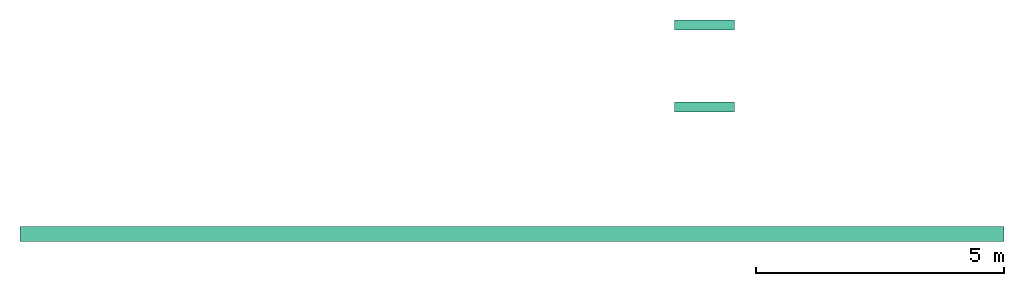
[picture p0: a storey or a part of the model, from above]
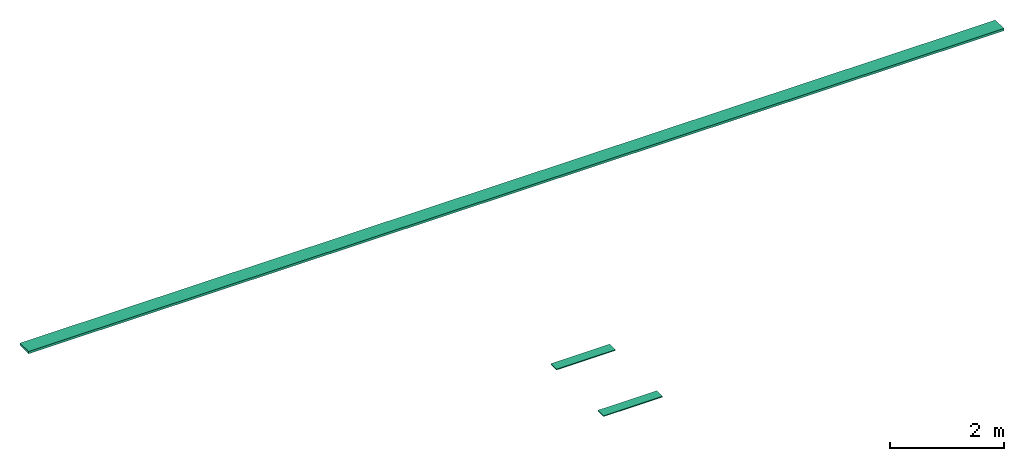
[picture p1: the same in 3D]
Properties of the parts of a building model (IFC2X3)

# File
Description: ViewDefinition [CoordinationView_V2.0]
File name: 20-10
Time: 2021-08-31T15:09:17
Written by: The EXPRESS Data Manager Version 5.02.0100.07 : 28 Aug 2013
Made in: 20200210_1400(x64) - Exporter 20.2.12.1 - Alternate UI 20.2.12.1
Comment: STEP Physical File produced by: The EXPRESS Data Manager Version 5.02.0100.07 : 28 Aug 2013 * Module: EDMstepFileFactory/EDMstandAlone * Creation date: Tue Aug 31 15:09:17 2021 * Host: KAWESQAR * Database: C:\Users\MANONB~1\AppData\Local\Temp\185624fe-82f3-48ab-880a-5ea0e2c92366\1c60d298-b767-46ab-aa57-350fe60cc4c5\ifc * Database version: 5507 * Database creation date: Tue Aug 31 15:09:05 2021 * Schema: IFC2X3 * Model: DataRepository.ifc * Model creation date: Tue Aug 31 15:09:05 2021 * Header model: DataRepository.ifc_HeaderModel * Header model creation date: Tue Aug 31 15:09:05 2021 * EDMuser: sdai-user * EDMgroup: sdai-group * License ID and type: 5605 : Permanent license. Expiry date: * EDMstepFileFactory options: 020000

# IfcProject, 20-10
LongName: OPERATION

# IfcSite, Default
RefLatitude: 48, 51, 57, 604064; RefLongitude: 2, 19, 58, 799800; RefElevation: 0 m

# IfcBuilding
Pset_BuildingCommon - NumberOfStoreys: 10
Pset_ProductRequirements - Category: Project Information

# IfcBuildingStorey: Level:Pointe 8 mm, 03_R+2_EL
LongName: 03_R+2_EL; Elevation: 7.83 m
Pset_ProductRequirements - Name: 03_R+2_EL; Category: Levels
Pset_AirSideSystemInformation - Name: 03_R+2_EL

# IfcBuildingStorey: Niveau:911002-NIV_nom.topo (6)
Pset_ProductRequirements - Category: Levels
Name | LongName | Elevation (m) | Pset_AirSideSystemInformation, Name = Pset_ProductRequirements, Name
S02 | S02 | -4.62 | STR-SS01 Fini
S01 | S01 | -0.4 | STR-FOND RDC
S01 | S01 | -0.06 | STR-RDC Brut
S01 | S01 | 0 | STR-RDC Fini
01 | 01 | 4.27 | STR-R+1
01 | 01 | 7.55 | STR-R+2

# IfcBuildingElementProxy: TD (5)
Type - Pset_BuildingElementProxyCommon - Reference: TD
Type - Pset_ProductRequirements - Category: EL_FR_PANEL_RECTANGLE
Type - Pset_QuantityTakeOff - Reference: TD
Pset_BuildingElementProxyCommon - sets with these values: 2
Pset_ProductRequirements - Category: Electrical Equipment
Name (Tableau divisionaire:...) | In
TD 0.1:7791674 | S02
TD 0.2:8645110 | S02
TD 1.2:8681680 | 01
TD 1.1:8715392 | 01
TD 2.1:8715395 | 03_R+2_EL

# IfcBuildingElementProxy: TGBT, TGBT:TGBT, 230 V/400 V, Three Phase, 4 Wires, Star:7914592
In: S02
Type - Pset_BuildingElementProxyCommon - Reference: TGBT
Type - Pset_ProductRequirements - Category: EL_FR_PANEL_RECTANGLE
Type - Pset_QuantityTakeOff - Reference: TGBT
Pset_BuildingElementProxyCommon - sets with these values: 2
Pset_ProductRequirements - Category: Electrical Equipment

# IfcBuildingElementProxy: VDA - Designed for circulation applications with switches and routers - 42U - 2000x600x1000, IT-racks_Schneider-Electric_Actassi_VDA -Functional-and-adapted-for-evolution:VDA - Designed for circulation applications with switches and routers - 42U - 2000x600x1000:8654036
In: S02
Type - Material: UHMW, Black, Glass, RAL 7035, Schneider Clearance Material
Type - Pset_BuildingElementProxyCommon - Reference: VDA - Designed for circulation applications with switches and routers - 42U - 2000x600x1000
Type - Pset_ManufacturerTypeInformation - Manufacturer: © Schneider Electric
Type - Pset_ProductRequirements - Category: Electrical Equipment
Type - Pset_QuantityTakeOff - Reference: VDA - Designed for circulation applications with switches and routers - 42U - 2000x600x1000
Pset_BuildingElementProxyCommon - sets with these values: 2

# IfcDistributionControlElement: Incendie_Bapi, INT_BAPI:Incendie_Bapi:7913407
In: S02
Type - Material: Color RGB 060-060-060, Color RGB 192-192-192, Color RGB 165-165-165
Pset_ProductRequirements - Category: Fire Alarm Devices
Pset_QuantityTakeOff - Reference: Incendie_Bapi

# IfcDistributionControlElement: Incendie_Centrale Incendie, INT_Centrale Incendie:Incendie_Centrale Incendie:8747964
In: S01
Pset_ProductRequirements - Category: Fire Alarm Devices
Pset_QuantityTakeOff - Reference: Incendie_Centrale Incendie

# IfcDistributionControlElement: Incendie_Diffuseur sonore (7)
Type - Material: Default grid, White Plastic
Pset_ProductRequirements - Category: Fire Alarm Devices
Pset_QuantityTakeOff - Reference: Incendie_Diffuseur sonore
Name (INT_DIffuseur sonore:Incendie_Diffuseur sonore:...) | In
8742318 | S01
8742320 | S01
8742322 | 01
8742324 | 01
8742326 | S02
8742328 | S02
8742329 | 03_R+2_EL

# IfcDistributionControlElement: Incendie_Déclenheur manuel (10)
Pset_ProductRequirements - Category: Fire Alarm Devices
Pset_QuantityTakeOff - Reference: Incendie_Déclenheur manuel
Name (INT_Déclenheur manuel:Incendie_Déclenheur manuel:...) | In
8719832 | S01
8719834 | S01
8719836 | S01
8719840 | 01
8719841 | 01
8719847 | 03_R+2_EL
8719848 | 03_R+2_EL
8756174 | S02
8756181 | S02
8756355 | S02

# IfcDistributionControlElement: Incendie_Flash (9)
Type - Material: Red plastic
Pset_ProductRequirements - Category: Fire Alarm Devices
Pset_QuantityTakeOff - Reference: Incendie_Flash
Name (INT_Flash:Incendie_Flash:...) | In
7744268 | 01
7744298 | 01
7789376 | S01
7789378 | S01
7790916 | S01
7796727 | S02
7796759 | S02
8666191 | 01
8666193 | 01

# IfcDistributionPort (1167)
Description: Flow; FlowDirection: SOURCEANDSINK
Name
InPort_7741705
OutPort_7742182
InPort_7742182
OutPort_7742196
Port_8683754
Port_8741130
Port_7744198
Port_8741123
Port_8741122
Port_7744183
Port_8741120
Port_7744125
Port_8741121
Port_7744142
Port_8741125
Port_7744254
Port_8741124
Port_7744211
Port_7744268
Port_7744298
Port_7744357
2 x Port_7744402
Port_7744631
Port_7744660
Port_7744688
Port_7744747
Port_7744756
Port_7744834
Port_7744846
2 x Port_7769064
Port_7769260
InPort_7769260
2 x OutPort_7778175
2 x Port_7769269
Port_7777599
Port_7777611
Port_7777712
Port_7777721
Port_7777762
Port_7777803
Port_7777885
2 x Port_7777949
Port_7777958
Port_7777965
Port_7777990
Port_7778025
Port_7778034
Port_7778035
Port_7778163
3 x InPort_7778163
OutPort_7876509
OutPort_8675102
Port_7778212
InPort_7778212
2 x OutPort_7778231
3 x InPort_7778221
OutPort_8675103
Port_7778221
2 x OutPort_7913418
Port_7785804
Port_7785842
Port_7785863
Port_7785870
Port_7785947
Port_7785954
Port_7789052
Port_7789136
Port_7789358
InPort_7789362
OutPort_7791303
Port_8740919
Port_7791514
Port_8740922
Port_7791554
Port_8740915
Port_7791263
Port_7789376
Port_7789378
Port_7789380
Port_7789384
Port_7789387
Port_7790916
Port_7791248
Port_8740914
InPort_7791303
OutPort_7791401
Port_7791540
Port_8740921
InPort_7791401
2 x OutPort_7791412
InPort_7791411
Port_7791674
2 x Port_7792699
2 x Port_7792700
Port_7792762
Port_7792832
Port_7792934
Port_7793028
Port_7793156
Port_8740822
Port_7795050
2 x InPort_7793805
OutPort_7793830
OutPort_7793816
Port_7795005
Port_8740819
InPort_7793865
OutPort_7793880
Port_8740825
Port_7795091
InPort_7793897
OutPort_7793899
Port_8740828
Port_7795136
Port_7795076
Port_8740824
Port_7795063
Port_8740823
Port_7795254
Port_7795328
Port_7795365
Port_7795432
Port_7795881
Port_7795892
Port_7795962
Port_8740829
Port_7796375
Port_7796386
Port_8740830
Port_8740831
Port_7796458
Port_8740832
Port_7796549
Port_7796560
Port_8740833
Port_7796626
Port_7796727
Port_7796759
Port_7796838
Port_7796843
Port_7810207
Port_8740835
Port_7810208
Port_8740836
Port_7876471
Port_7876472
Port_7876473
Port_7876475
Port_7876484
InPort_7876486
OutPort_7876488
Port_8740861
Port_7876490
InPort_7876492
OutPort_7876494
Port_8740867
Port_7876508
Port_7876507
Port_8740866
InPort_7876497
OutPort_7876499
Port_8740865
Port_7876506
Port_7876509
InPort_7876509
OutPort_7913447
InPort_7876520
2 x OutPort_7913417
Port_7876520
Port_7877531
InPort_7901673
OutPort_7901679
Port_7901717
Port_8740871
Port_7901730
Port_8740876
2 x Port_7901684
Port_7901685
Port_7901687
Port_7901688
Port_7901689
Port_7901690
Port_7901691
Port_7901692
Port_7901728
InPort_7901718
OutPort_7901719
Port_8740874
Port_8740875
Port_7901729
Port_7901731
InPort_7901723
OutPort_7901724
Port_8740877
Port_8740878
Port_7901732
2 x Port_7901733
Port_7901734
Port_7901736
Port_7901737
Port_7901738
Port_7901739
Port_7901740
Port_7901741
2 x Port_7901742
Port_7901743
Port_7901745
Port_7901746
Port_7901747
Port_7901748
Port_7901749
Port_7901750
2 x Port_7901751
Port_7901752
Port_7901754
Port_7901755
Port_7901756
Port_7901757
Port_7901758
Port_7901759
2 x Port_7901801
Port_7901802
Port_7901804
Port_7901805
Port_7901806
Port_7901807
Port_7901808
Port_7901809
Port_8740880
Port_7902684
Port_7902669
Port_8740879
Port_7902081
Port_7902106
Port_7902208
Port_7902437
Port_7913393
Port_7913400
Port_7913403
Port_7913406
Port_7913407
2 x InPort_7913409
2 x OutPort_7913464
OutPort_7913458
2 x InPort_7913410
OutPort_7913459
2 x OutPort_7913463
2 x InPort_7913411
2 x OutPort_7913415
2 x InPort_7913414
2 x OutPort_7913420
2 x InPort_7913416
InPort_7913417
2 x InPort_7913423
OutPort_7913431
InPort_7913431
OutPort_7913433
InPort_7913433
2 x OutPort_7913435
2 x InPort_7913434
2 x OutPort_7913437
2 x InPort_7913436
2 x OutPort_7913440
2 x InPort_7913439
2 x OutPort_7913446
2 x InPort_7913445
2 x OutPort_7913448
InPort_7913447
2 x Port_7913458
InPort_7913458
OutPort_8645113
InPort_7913459
OutPort_8645114
2 x Port_7913459
Port_7914592
Port_8750771
2 x InPort_7914593
OutPort_7914599
2 x OutPort_8734681
Port_8270898
Port_8270900
Port_8277180
Port_8277182
Port_8277183
InPort_8277184
2 x OutPort_8277198
Port_8277184
2 x InPort_8277187
2 x OutPort_8277191
Port_8277190
InPort_8277190
Port_8277192
Port_8277193
Port_8277194
Port_8277195
Port_8277199
Port_8277200
Port_8277201
Port_8277202
Port_8277203
Port_8277204
Port_8277205
Port_8277206
Port_8277207
Port_8277208
Port_8277209
Port_8277210
Port_8277211
Port_8277212
Port_8277213
Port_8277214
Port_8277215
Port_8277216
Port_8277217
Port_8277218
Port_8277219
Port_8277358
Port_8277359
Port_8277360
Port_8277361
Port_8277362
Port_8277363
Port_8277364
Port_8277487
Port_8277488
Port_8277489
Port_8277490
Port_8277491
Port_8277492
Port_8277493
Port_8277500
Port_8277501
Port_8277502
Port_8277503
Port_8277504
Port_8277505
Port_8277506
Port_8277512
Port_8277513
Port_8277514
Port_8277515
Port_8277516
Port_8277517
Port_8277518
Port_8277529
Port_8277530
Port_8277531
Port_8277532
Port_8277533
Port_8277534
Port_8277535
Port_8277570
Port_8277633
Port_8281313
Port_8281360
Port_8281379
Port_8281695
Port_8281696
Port_8281786
Port_8289758
Port_8297719
Port_8297810
Port_8297825
Port_8297848
Port_8317719
Port_8317720
Port_8317721
Port_8318129
Port_8318138
Port_8318201
Port_8318212
Port_8318221
Port_8318230
Port_8318244
Port_8318246
Port_8318248
Port_8318250
Port_8318252
Port_8318254
Port_8318371
Port_8318383
InPort_8318572
OutPort_8318608
InPort_8318608
OutPort_8318626
Port_8318745
Port_8740956
Port_8319005
Port_8319007
Port_8319008
Port_8319009
Port_8319034
InPort_8319157
OutPort_8319195
InPort_8319195
OutPort_8320982
Port_8321050
Port_8321082
Port_8321099
Port_8321119
Port_8321156
Port_8632143
Port_8632144
Port_8632147
Port_8632148
Port_8632155
Port_8632162
Port_8632166
Port_8632167
Port_8632168
Port_8632169
Port_8632171
Port_8632175
Port_8632177
Port_8632179
Port_8632181
Port_8632204
Port_8632205
Port_8645110
Port_8645113
Port_8645114
2 x Port_8645142
Port_8645143
Port_8645145
Port_8645146
Port_8645147
Port_8645148
Port_8645149
Port_8645334
Port_8645335
Port_8645336
Port_8645579
Port_8645580
Port_8645581
2 x Port_8645821
Port_8645822
Port_8645824
Port_8645825
Port_8645826
Port_8645827
Port_8645828
Port_8645892
Port_8645905
Port_8645922
Port_8645923
Port_8645931
Port_8645972
Port_8645983
Port_8646006
Port_8646044
Port_8646108
Port_8646135
Port_8646147
Port_8646162
Port_8646165
Port_8646168
Port_8646170
Port_8650504
Port_8650516
Port_8650518
Port_8650525
2 x Port_8650588
Port_8650589
Port_8650591
Port_8650592
Port_8650593
Port_8650594
Port_8650595
Port_8650602
Port_8650604
Port_8650605
Port_8650607
Port_8650609
InPort_8650686
OutPort_8650687
InPort_8650687
OutPort_8650688
InPort_8650811
OutPort_8650812
Port_8650871
Port_8650873
Port_8650874
Port_8650875
Port_8650876
Port_8650877
Port_8650883
Port_8650884
Port_8650885
Port_8650886
Port_8650887
Port_8650888
2 x Port_8665642
Port_8665645
Port_8665646
Port_8665647
Port_8665648
Port_8665649
Port_8665650
2 x Port_8665852
Port_8665855
Port_8665856
Port_8665857
Port_8665858
Port_8665859
Port_8665860
2 x Port_8665933
Port_8665937
Port_8665940
Port_8665941
Port_8666030
Port_8741018
Port_8666187
Port_8666186
Port_8741017
Port_8741015
Port_8666182
Port_8741016
Port_8666183
Port_8666190
Port_8741020
Port_8741019
Port_8666188
Port_8666191
Port_8666193
Port_8666195
Port_8666197
2 x Port_8667869
Port_8667871
Port_8667872
Port_8667873
Port_8667874
Port_8667875
Port_8667876
Port_8674193
InPort_8667969
OutPort_8667970
Port_8741045
InPort_8668206
OutPort_8668207
InPort_8668221
OutPort_8668222
InPort_8668234
OutPort_8668235
InPort_8668245
OutPort_8668246
InPort_8668327
OutPort_8668328
InPort_8668354
OutPort_8668355
InPort_8668381
OutPort_8668382
Port_8668447
Port_8668458
Port_8668472
Port_8668496
Port_8741046
Port_8674273
Port_8674291
Port_8674303
Port_8674603
Port_8741048
Port_8674588
Port_8741047
Port_8674676
Port_8674997
Port_8675016
Port_8675026
Port_8675043
Port_8675046
Port_8675049
Port_8675051
Port_8675102
Port_8675103
2 x InPort_8675104
2 x OutPort_8880330
2 x OutPort_8824633
2 x Port_8675105
2 x Port_8681093
Port_8681095
Port_8681096
Port_8681097
Port_8681098
Port_8681099
Port_8681100
2 x Port_8681101
Port_8681103
Port_8681104
Port_8681105
Port_8681106
Port_8681107
Port_8681108
2 x Port_8681109
Port_8681111
Port_8681112
Port_8681113
Port_8681114
Port_8681115
Port_8681116
Port_8681117
Port_8681118
Port_8681119
Port_8681120
Port_8681121
Port_8681122
Port_8681123
Port_8681124
Port_8681125
Port_8681126
Port_8681127
Port_8681128
Port_8681129
Port_8681130
Port_8681131
Port_8681132
Port_8681133
Port_8681134
Port_8681139
Port_8681140
2 x Port_8681143
Port_8681145
Port_8681146
Port_8681147
Port_8681148
2 x Port_8681154
Port_8681156
Port_8681157
Port_8681158
Port_8681159
Port_8681160
Port_8681161
2 x Port_8681162
Port_8681164
Port_8681165
Port_8681166
Port_8681167
Port_8681168
Port_8681169
2 x Port_8681170
Port_8681172
Port_8681173
Port_8681174
Port_8681175
Port_8681176
Port_8681177
2 x Port_8681178
Port_8681180
Port_8681181
Port_8681182
Port_8681183
Port_8681184
Port_8681185
Port_8681186
Port_8681187
Port_8681188
Port_8681189
Port_8681190
Port_8681191
Port_8681192
Port_8681193
Port_8681194
Port_8681195
Port_8681196
Port_8681197
2 x Port_8681198
Port_8681200
Port_8681201
Port_8681202
Port_8681203
Port_8681204
Port_8681205
2 x Port_8681207
Port_8681209
Port_8681210
Port_8681211
Port_8681212
Port_8681213
Port_8681214
2 x Port_8681215
Port_8681217
Port_8681218
Port_8681219
Port_8681220
Port_8681221
Port_8681222
2 x Port_8681223
Port_8681225
Port_8681226
Port_8681227
Port_8681228
2 x Port_8681229
Port_8681231
Port_8681232
Port_8681233
Port_8681234
Port_8681235
Port_8681236
InPort_8681350
OutPort_8681396
InPort_8681354
OutPort_8681355
Port_8681362
Port_8741083
Port_8681465
Port_8741084
Port_8741090
Port_8681495
Port_8681502
InPort_8681538
OutPort_8681539
Port_8741096
InPort_8681547
OutPort_8822909
Port_8681567
Port_8681573
Port_8681579
Port_8681602
Port_8681608
Port_8681614
Port_8681620
Port_8681626
Port_8681680
2 x InPort_8683758
OutPort_8683759
2 x OutPort_8688980
InPort_8683759
OutPort_8683768
InPort_8683763
OutPort_8683764
InPort_8683764
Port_8688659
2 x InPort_8688800
2 x OutPort_8688810
OutPort_8688801
2 x InPort_8688805
OutPort_8688806
2 x InPort_8688830
2 x OutPort_8688840
OutPort_8688831
InPort_8688835
OutPort_8688836
InPort_8688836
InPort_8691844
OutPort_8691845
Port_8691853
Port_8691888
Port_8710521
2 x Port_8710523 | Group: M531 11
Port_8710527
Port_8710529
Port_8710531
Port_8710533
Port_8710535
Port_8710537
Port_8710539
Port_8710541
Port_8710543
Port_8710546
Port_8710551
Port_8710555
Port_8715392
Port_8715395
Port_8715397
Port_8715398
Port_8715399
Port_8715400
Port_8715401
Port_8715402
Port_8715403
Port_8715404
Port_8715405
Port_8715406
Port_8715407
Port_8715408
Port_8715409
Port_8715410
Port_8715411
Port_8715412
Port_8715413
Port_8715414
Port_8715415
Port_8715416
Port_8715417
Port_8715418
Port_8715419
Port_8715420
Port_8715421
Port_8715422
Port_8715423
Port_8715424
Port_8715425
Port_8715426
Port_8715427
Port_8715428
Port_8715429
Port_8715430
Port_8719832
Port_8719834
Port_8719836
Port_8719840
Port_8719841
Port_8719847
Port_8719848
Port_8719849
Port_8719852
Port_8740893
Port_8723903
Port_8723904
Port_8740894
Port_8723905
Port_8740895
Port_8723906
Port_8734037
Port_8734039
Port_8734041
Port_8734043
Port_8734045
Port_8734212
InPort_8734679
Port_8740897
Port_8734692
Port_8750758
Port_8742318
Port_8742320
Port_8742322
Port_8742324
Port_8742326
Port_8742328
Port_8742329
Port_8742353
Port_8747907
Port_8747913
Port_8747919
Port_8747964
Port_8748015
Port_8748039
Port_8750186
Port_8750603
2 x Port_8750664 | Group: M531 12
2 x Port_8750677 | Group: M531 13
Port_8750823
Port_8750847
Port_8750853
Port_8750859
InPort_8751408
2 x OutPort_8751423
Port_8751408
2 x InPort_8751417
2 x OutPort_8751441
2 x InPort_8751427
2 x OutPort_8751470
InPort_8751458
Port_8751458
Port_8753972
Port_8753975
Port_8753982
Port_8753983
Port_8753986
Port_8753987
Port_8753990
Port_8753991
Port_8755647
InPort_8755505
OutPort_8755559
Port_8756728
InPort_8755559
OutPort_8755570
InPort_8755570
OutPort_8755578
2 x Port_8755763
Port_8755764
Port_8755766
Port_8755767
Port_8755768
Port_8755769
Port_8755770
Port_8755771
Port_8755869
Port_8755871
Port_8755873
Port_8755917
Port_8755945
Port_8755970
Port_8756174
Port_8756181
Port_8756355
Port_8767871
Port_8767872
Port_8767957
Port_8768032
Port_8768043
Port_8768068
Port_8768084
Port_8768119
Port_8768458
Port_8768469
Port_8768478
Port_8768487
Port_8768496
Port_8768507
Port_8768518
Port_8768533
Port_8768542
Port_8768551
Port_8768560
Port_8768569
Port_8768580
Port_8768589
Port_8768598
2 x Port_8798240
Port_8798241
Port_8798243
Port_8798244
Port_8798245
Port_8798246
Port_8798247
Port_8798248
Port_8798345
Port_8823341
2 x Port_8798410
Port_8798412
Port_8798413
Port_8798414
Port_8798415
Port_8798416
Port_8798417
Port_8798418
InPort_8798577
OutPort_8798578
Port_8798621
Port_8798687
Port_8798713
Port_8798722
Port_8798731
Port_8798742
Port_8798753
Port_8798764
Port_8798775
Port_8798786
Port_8798795
Port_8798806
Port_8798817
Port_8798826
Port_8798835
Port_8798848
Port_8798857
Port_8798870
Port_8821109
Port_8821135
Port_8821144
Port_8821153
Port_8821162
Port_8821171
Port_8821180
Port_8821304
Port_8821330
Port_8821364
Port_8821366
Port_8821391
Port_8821392
Port_8821400
Port_8821401
Port_8821415
2 x InPort_8821556
2 x OutPort_8821734
2 x OutPort_8821755
2 x InPort_8821626
2 x OutPort_8821657
2 x InPort_8821648
2 x OutPort_8821672
2 x InPort_8821660
2 x OutPort_8821683
Port_8821675
InPort_8821675
InPort_8821744
Port_8821744
Port_8822402
Port_8822403
Port_8822413
Port_8822414
Port_8822533
Port_8822534
Port_8822545
Port_8822546
Port_8822557
Port_8822558
Port_8822569
Port_8822570
2 x InPort_8824520
2 x OutPort_8880285
2 x OutPort_8824594
2 x Port_8824521
2 x InPort_8824582
2 x OutPort_8824607
2 x InPort_8824597
2 x OutPort_8824636
2 x InPort_8824610
Port_8828758
Port_8828759
Port_8828760
Port_8828761
Port_8828762
Port_8828763
Port_8828764
Port_8828765
Port_8828766
Port_8828767
Port_8828768
Port_8828769
Port_8828770
Port_8828771
Port_8828772
Port_8828773
Port_8828774
Port_8828775
Port_8828776
Port_8828777
Port_8828778
Port_8828779
Port_8828780
Port_8828781
Port_8828782
Port_8828783
Port_8828784
Port_8828786
Port_8828787
Port_8865605
Port_8865611
Port_8866616
Port_8866637
Port_8866665
Port_8866804
Port_8866954
Port_8866969
Port_8877106
Port_8877118
Port_8877124
Port_8877139
Port_8877145
Port_8877151
Port_8877314
2 x InPort_8879930
2 x OutPort_8880289
2 x OutPort_8880291
2 x InPort_8879931
2 x OutPort_8880287
2 x InPort_8879933
Port_8880235
InPort_8880235
2 x InPort_8880314
2 x OutPort_8880333
Port_8880315
InPort_8880315

# IfcFlowFitting: E_Bend_Horizontal_CA_Generic_MEPcontent (8)
Pset_DistributionFlowElementCommon - Reference: E_Bend_Horizontal_CA_Generic_MEPcontent; sets with these values: 2
Pset_ProductRequirements - Category: Cable Tray Fittings
Name (E_Bend_Horizontal_CA_Generic_MEPcontent:E_Bend_Horizontal_CA_Generic_MEPcontent:...) | In
7913415 | S02
7913420 | S02
7913431 | S02
7913435 | S02
7913463 | S02
7913464 | S02
8277191 | S01
8277198 | S01

# IfcFlowFitting: E_Bend_Vertical_Inside_CA_Generic_MEPcontent (8)
Pset_DistributionFlowElementCommon - Reference: E_Bend_Vertical_Inside_CA_Generic_MEPcontent; sets with these values: 2
Pset_ProductRequirements - Category: Cable Tray Fittings
Name (E_Bend_Vertical_Inside_CA_Generic_MEPcontent:E_Bend_Vertical_Inside_CA_Generic_MEPcontent:...) | In
7913437 | S02
7913448 | S02
8751441 | S02
8824607 | 01
8824636 | 01
8880287 | 01
8880291 | 01
8880333 | 01

# IfcFlowFitting: E_Bend_Vertical_Outside_CA_Generic_MEPcontent (11)
Pset_DistributionFlowElementCommon - Reference: E_Bend_Vertical_Outside_CA_Generic_MEPcontent; sets with these values: 2
Pset_ProductRequirements - Category: Cable Tray Fittings
Name (E_Bend_Vertical_Outside_CA_Generic_MEPcontent:E_Bend_Vertical_Outside_CA_Generic_MEPcontent:...) | In
7778175 | 03_R+2_EL
7778231 | 03_R+2_EL
7913440 | S02
7913446 | S02
8751423 | S02
8751470 | S02
8824594 | 01
8824633 | 01
8880285 | 01
8880289 | 01
8880330 | 01

# IfcFlowFitting: E_Connection_CA_Generic_MEPcontent, E_Connection_CA_Generic_MEPcontent:E_Connection_CA_Generic_MEPcontent:8824521
In: 01
Pset_DistributionFlowElementCommon - Reference: E_Connection_CA_Generic_MEPcontent; sets with these values: 2
Pset_ProductRequirements - Category: Cable Tray Fittings

# IfcFlowFitting: E_E6120_Lightning Conductor_Bend_MEPcontent (5)
In: S02
Pset_DistributionFlowElementCommon - Reference: E_E6120_Lightning Conductor_Bend_MEPcontent; sets with these values: 2
Pset_ProductRequirements - Category: Conduit Fittings
Name (E_Lightning Conductor_Bend_MEPcontent:E_E6120_Lightning Conductor_Bend_MEPcontent:...)
8821657
8821672
8821683
8821734
8821755

# IfcFlowFitting: E_Tee_Horizontal_CA_Generic_MEPcontent, E_Tee_Horizontal_CA_Generic_MEPcontent:E_Tee_Horizontal_CA_Generic_MEPcontent:7913417
In: S02
Pset_DistributionFlowElementCommon - Reference: E_Tee_Horizontal_CA_Generic_MEPcontent; sets with these values: 2
Pset_ProductRequirements - Category: Cable Tray Fittings

# IfcFlowFitting: M_Bend_Circular_MEPcontent_Cuivre_2M (3)
In: S02
Type - PredefinedType: BEND
Pset_DistributionFlowElementCommon - Reference: M_Bend_Circular_MEPcontent_Cuivre_2M; sets with these values: 2
Pset_ManufacturerTypeInformation - Manufacturer: Unspecified
Pset_ProductRequirements - Category: Pipe Fittings
Name (M_Bend_Circular_MEPcontent_Cuivre_2M:M_Bend_Circular_MEPcontent_Cuivre_2M:...) | Group
8710523 | M531 11
8750664 | M531 12
8750677 | M531 13

# IfcFlowSegment: Cable Tray with Fittings:Chemins de câbles en treillis_Chemins de câbles en treillis (39)
Pset_DistributionFlowElementCommon - Reference: Chemins de câbles en treillis_Chemins de câbles en treillis; sets with these values: 2
Pset_FlowSegmentDuctSegment - sets with these values: 2
Pset_ManufacturerTypeInformation - Manufacturer: Unspecified
Pset_ProductRequirements - Category: Cable Trays
Name (Cable Tray with Fittings:Chemins de câbles en treillis_Chemins de câbles en treillis:...) | In | Length (m)
7769260 | 01 | 12.6219
7778163 | 01 | 14.0779
7778212 | 01 | 12.6219
7778221 | 01 | 14.5509
7792699 | S01 | 19.8335
7792700 | S02 | 19.9384
7876509 | S02 | 12.653
7876520 | S02 | 8.0316
7913409 | S02 | 5.12579
7913410 | S02 | 4.26001
7913411 | S02 | 3.97459
7913414 | S02 | 16.6468
7913416 | S02 | 3.37523
7913418 | S02 | 4.02137
7913423 | S02 | 5.98814
7913433 | S02 | 20.6547
7913434 | S02 | 3.9629
7913436 | S02 | 0.695139
7913439 | S02 | 0.371697
7913445 | S02 | 0.152074
7913447 | S02 | 0.509213
7913458 | 01 | 11.456
7913459 | 01 | 11.456
8645113 | S01 | 15.3977
8645114 | S01 | 15.3977
8675102 | 01 | 19.8335
8675103 | S01 | 19.8335
8675104 | 01 | 3.01401
8675105 | 01 | 15.3977
8824520 | 01 | 1.66598
8824582 | 01 | 0.205081
8824597 | 01 | 1.23808
8824610 | 01 | 0.205062
8879930 | 01 | 0.205081
8879931 | 01 | 1.23808
8879933 | 01 | 0.205081
8880235 | 01 | 6.09454
8880314 | 01 | 0.205056
8880315 | 01 | 1.23808

# IfcFlowSegment: Cable Tray with Fittings:Goulottes de câbles indéfini_Goulottes de câbles (39)
Pset_DistributionFlowElementCommon - Reference: Goulottes de câbles indéfini_Goulottes de câbles; sets with these values: 2
Pset_FlowSegmentDuctSegment - sets with these values: 2
Pset_ManufacturerTypeInformation - Manufacturer: Unspecified
Pset_ProductRequirements - Category: Cable Trays
Name (Cable Tray with Fittings:Goulottes de câbles indéfini_Goulottes de câbles:...) | In | Length (m)
7744402 | 01 | 1.992
7769064 | 01 | 2.247
7769269 | 01 | 6.768
7777949 | 01 | 6.768
7901684 | S02 | 2.834
7901733 | S02 | 2.66
7901742 | S02 | 2.667
7901751 | S02 | 3.78703
7901801 | S02 | 3.146
8277184 | S01 | 12.9969
8277187 | S01 | 7.90084
8277190 | S01 | 12.9209
8645142 | S01 | 2.041
8645821 | S01 | 6.873
8650588 | 01 | 5.6
8665642 | 01 | 2.749
8665852 | 01 | 3.916
8665933 | 01 | 3.8836
8667869 | 01 | 4.03
8681093 | 01 | 6.736
8681101 | 01 | 3.916
8681109 | 01 | 6.737
8681143 | 01 | 2.739
8681154 | 01 | 3.916
8681162 | 01 | 7.912
8681170 | 01 | 2.419
8681178 | 01 | 2.716
8681198 | 01 | 2.419
8681207 | 01 | 2.749
8681215 | 01 | 7.892
8681223 | 01 | 3.8836
8681229 | 01 | 1.461
8751408 | S02 | 4.69455
8751417 | S02 | 1.0201
8751427 | S02 | 4.3511
8751458 | S02 | 0.289548
8755763 | 01 | 3.61246
8798240 | S01 | 2.859
8798410 | 01 | 1.727

# IfcFlowSegment: Conduit without Fittings:Conduit (6)
In: S02
Pset_DistributionFlowElementCommon - Reference: Conduit; sets with these values: 2
Pset_FlowSegmentDuctSegment - sets with these values: 2
Pset_ProductRequirements - Category: Conduits
Name (Conduit without Fittings:Conduit:...) | Length (m)
8821556 | 3.09092
8821626 | 0.759408
8821648 | 2.24586
8821660 | 3.04233
8821675 | 0.879768
8821744 | 2.32981

# IfcFlowTerminal: Attente (71)
Pset_DistributionFlowElementCommon - Reference: Attente; sets with these values: 2
Pset_ProductRequirements - Category: Electrical Fixtures
Name (INT_Attente électrique:Attente:...) | In
7789052 | 01
7789384 | S01
7796838 | S02
8710521 | S02
8710527 | S02
8710529 | S02
8710531 | S02
8710533 | S02
8710535 | S02
8710537 | S02
8710539 | S02
8710541 | S01
8710543 | S01
8710546 | 01
8710551 | 03_R+2_EL
8710555 | 03_R+2_EL
8719852 | S02
8723906 | S02
8734037 | S01
8734039 | 01
8734041 | 03_R+2_EL
8734043 | 03_R+2_EL
8734045 | 03_R+2_EL
8767871 | 03_R+2_EL
8767872 | 03_R+2_EL
8767957 | S02
8768032 | S02
8768043 | S02
8768068 | S02
8768084 | S02
8768119 | S01
8768458 | S01
8768469 | S01
8768478 | S01
8768487 | S01
8768496 | S01
8768507 | S01
8768518 | S01
8768533 | S01
8768542 | S01
8768551 | S01
8768560 | S01
8768569 | S01
8768580 | S01
8768589 | S01
8768598 | S01
8798687 | 01
8798713 | 01
8798722 | 01
8798731 | 01
8798742 | 01
8798753 | 01
8798764 | 01
8798775 | 01
8798786 | 01
8798795 | 01
8798806 | 01
8798817 | 01
8798826 | 01
8798835 | 01
8798848 | 01
8798857 | 01
8798870 | 01
8821109 | 03_R+2_EL
8821135 | 03_R+2_EL
8821144 | 03_R+2_EL
8821153 | 03_R+2_EL
8821162 | 03_R+2_EL
8821171 | 03_R+2_EL
8821180 | 03_R+2_EL
8821415 | S02

# IfcFlowTerminal: BAEA Type 3 (2)
In: S01
Type - Material: Color RGB 225-225-149, Color RGB 165-165-165
Pset_DistributionFlowElementCommon - Reference: BAEA Type 3; sets with these values: 2
Pset_ProductRequirements - Category: Lighting Fixtures
Name (II_PREF_BAEA:BAEA Type 3:...)
8289758
8297719

# IfcFlowTerminal: BP IP21 (43)
Pset_DistributionFlowElementCommon - Reference: BP IP21; sets with these values: 2
Pset_ProductRequirements - Category: Lighting Devices
Name | In
INT_Inter BP:BP IP21:8723908 | S01
INT_Cmd BA:BP IP21:8733993 | S01
INT_Cmd BA:BP IP21:8733998 | S01
INT_Cmd BA:BP IP21:8733999 | S01
INT_Cmd BA:BP IP21:8734000 | S01
INT_Cmd BA:BP IP21:8734001 | S01
INT_Cmd BA:BP IP21:8734002 | S01
INT_Cmd BA:BP IP21:8734003 | S01
INT_Cmd BA:BP IP21:8734004 | S01
INT_Cmd BA:BP IP21:8734005 | S01
INT_Cmd BA:BP IP21:8734006 | 01
INT_Cmd BA:BP IP21:8734008 | 01
INT_Cmd BA:BP IP21:8734009 | 01
INT_Cmd BA:BP IP21:8734011 | 01
INT_Cmd BA:BP IP21:8734012 | 01
INT_Cmd BA:BP IP21:8734013 | 01
INT_Cmd BA:BP IP21:8734014 | 01
INT_Cmd BA:BP IP21:8734016 | 01
INT_Cmd BA:BP IP21:8734018 | 01
INT_Cmd BA:BP IP21:8734019 | 01
INT_Cmd BA:BP IP21:8734020 | 01
INT_Cmd BA:BP IP21:8734022 | 01
INT_Cmd BA:BP IP21:8734023 | 01
INT_Cmd BA:BP IP21:8734024 | 01
INT_Cmd BA:BP IP21:8734026 | 01
INT_Cmd BA:BP IP21:8734027 | 03_R+2_EL
INT_Cmd BA:BP IP21:8734029 | 03_R+2_EL
INT_Cmd BA:BP IP21:8734030 | 03_R+2_EL
INT_Cmd BA:BP IP21:8734036 | 03_R+2_EL
INT_Cmd BA:BP IP21:8757446 | S02
INT_Cmd BA:BP IP21:8757468 | S02
INT_Cmd BA:BP IP21:8757615 | S02
INT_Cmd BA:BP IP21:8757793 | S02
INT_Cmd BA:BP IP21:8757800 | S02
INT_Cmd BA:BP IP21:8758039 | S02
INT_Cmd BA:BP IP21:8768624 | S01
INT_Cmd BA:BP IP21:8798009 | S01
INT_Cmd BA:BP IP21:8798011 | S01
INT_Cmd BA:BP IP21:8798017 | S01
INT_Cmd BA:BP IP21:8798018 | S01
INT_Cmd BA:BP IP21:8801330 | 03_R+2_EL
INT_Cmd BA:BP IP21:8801430 | 03_R+2_EL
INT_Cmd BA:BP IP21:8811316 | 03_R+2_EL

# IfcFlowTerminal: B_Réglete étanche (25)
Pset_DistributionFlowElementCommon - Reference: B_Réglete étanche; sets with these values: 2
Pset_ProductRequirements - Category: Lighting Fixtures
Name (II_PREF_Type B Réglette étanche:B_Réglete étanche:...) | In
7793730 | S02
7793805 | S02
7793816 | S02
7793830 | S02
7793865 | S02
7793880 | S02
7793897 | S02
7793899 | S02
7793910 | S02
7793925 | S02
7797838 | S02
7797846 | S02
7876486 | S02
7876488 | S02
7876492 | S02
7876494 | S02
7876497 | S02
7876499 | S02
7914593 | S02
7914599 | S02
8723878 | S02
8723880 | S02
8723882 | S02
8734679 | S01
8734681 | S01

# IfcFlowTerminal: Baie de brassage, INT_Baie de Brassage:Baie de brassage:8866969
In: S02
Pset_DistributionFlowElementCommon - Reference: Baie de brassage; sets with these values: 2
Pset_ProductRequirements - Category: Data Devices

# IfcFlowTerminal: CSS-UC-1_Video Package w/Universal Power Pack (2)
In: S02
Type - Classification: F1050900 Other Special Control& Instrumentation (Uniformat); Material: Plastic - Crestron Electronics - B-S - Black Smooth
Pset_DistributionFlowElementCommon - Reference: CSS-UC-1_Video Package w/Universal Power Pack; sets with these values: 2
Pset_ManufacturerTypeInformation - Manufacturer: Crestron Electronics, Inc.
Pset_ProductRequirements - Category: Communication Devices
Name (Digital_Media-Crestron-Mercury-CCS-UC-1:CSS-UC-1_Video Package w/Universal Power Pack:...)
8750186
8750603

# IfcFlowTerminal: Default (37)
Pset_DistributionFlowElementCommon - Reference: Default; sets with these values: 2
Pset_ProductRequirements - Category: Security Devices
Name (E_Reader_Badge 1_F_MEPcontent:Default:...) | In
7785804 | 01
7785842 | 01
7785863 | 01
7785870 | 01
7785947 | 01
7785954 | 01
8321082 | S01
8321099 | S01
8321119 | S01
8321156 | S01
8645931 | S01
8645972 | S01
8645983 | S01
8646006 | S01
8650602 | 01
8650604 | 01
8650605 | 01
8650607 | 01
8681567 | 01
8681573 | 01
8681579 | 01
8681602 | 01
8681608 | 01
8681614 | 01
8681620 | 01
8681626 | 01
8750823 | S02
8750847 | S02
8750853 | S02
8750859 | S02
8866954 | 01
8877106 | 01
8877118 | 01
8877124 | 01
8877139 | 01
8877145 | 01
8877151 | 01

# IfcFlowTerminal: Détecteur 360° (81)
Pset_DistributionFlowElementCommon - Reference: Détecteur 360°; sets with these values: 2
Pset_ProductRequirements - Category: Lighting Devices
Name | In
INT - Détecteur 360°:Détecteur 360°:7743920 | 01
INT - Détecteur 360°:Détecteur 360°:7744170 | 01
INT - Détecteur 360°:Détecteur 360°:7744179 | 01
INT - Détecteur 360°:Détecteur 360°:7744239 | 01
INT - Détecteur Luminosite:Détecteur 360°:7777485 | 01
INT - Détecteur Luminosite:Détecteur 360°:7777553 | 01
INT - Détecteur Luminosite:Détecteur 360°:7777923 | 01
INT - Détecteur Luminosite:Détecteur 360°:7777932 | 01
INT - Détecteur 360°:Détecteur 360°:7789366 | S01
INT - Détecteur 360°:Détecteur 360°:7789369 | S01
INT - Détecteur 360°:Détecteur 360°:7789370 | S01
INT - Détecteur 360°:Détecteur 360°:7789374 | S01
INT - Détecteur 360°:Détecteur 360°:7791039 | S01
INT - Détecteur 360°:Détecteur 360°:7796197 | S02
INT - Détecteur 360°:Détecteur 360°:7796416 | S02
INT - Détecteur 360°:Détecteur 360°:7796537 | S02
INT - Détecteur 360°:Détecteur 360°:7810191 | S02
INT - Détecteur 360°:Détecteur 360°:7810204 | S02
INT - Détecteur 360°:Détecteur 360°:7810206 | S02
INT - Détecteur 360°:Détecteur 360°:7810375 | S02
INT - Détecteur 360°:Détecteur 360°:7810749 | S02
INT - Détecteur 360°:Détecteur 360°:7810765 | S02
INT - Détecteur 360°:Détecteur 360°:7811263 | S02
INT - Détecteur Luminosite:Détecteur 360°:8297748 | S01
INT - Détecteur Luminosite:Détecteur 360°:8297791 | S01
INT - Détecteur Luminosite:Détecteur 360°:8645346 | S02
INT - Détecteur Luminosite:Détecteur 360°:8645535 | S02
INT - Détecteur Luminosite:Détecteur 360°:8645549 | S02
INT - Détecteur Luminosite:Détecteur 360°:8645556 | S02
INT - Détecteur Luminosite:Détecteur 360°:8645565 | S02
INT - Détecteur Luminosite:Détecteur 360°:8650577 | S02
INT - Détecteur 360°:Détecteur 360°:8666181 | 01
INT - Détecteur 360°:Détecteur 360°:8666184 | 01
INT - Détecteur 360°:Détecteur 360°:8666185 | 01
INT - Détecteur 360°:Détecteur 360°:8666189 | 01
INT - Détecteur Luminosite:Détecteur 360°:8667993 | S02
INT - Détecteur Luminosite:Détecteur 360°:8668445 | S02
INT - Détecteur Luminosite:Détecteur 360°:8668457 | S02
INT - Détecteur Luminosite:Détecteur 360°:8668471 | S02
INT - Détecteur Luminosite:Détecteur 360°:8668495 | S02
INT - Détecteur Luminosite:Détecteur 360°:8681361 | S02
INT - Détecteur Luminosite:Détecteur 360°:8681464 | S02
INT - Détecteur Luminosite:Détecteur 360°:8681501 | S02
INT - Détecteur Luminosite:Détecteur 360°:8681545 | S02
INT - Détecteur 360°:Détecteur 360°:8753998 | S02
INT - Détecteur 360°:Détecteur 360°:8754000 | S02
INT - Détecteur 360°:Détecteur 360°:8754002 | S02
INT - Détecteur 360°:Détecteur 360°:8754004 | S02
INT - Détecteur 360°:Détecteur 360°:8754007 | S02
INT - Détecteur 360°:Détecteur 360°:8754008 | S02
INT - Détecteur 360°:Détecteur 360°:8754009 | S02
INT - Détecteur 360°:Détecteur 360°:8754013 | S02
INT - Détecteur 360°:Détecteur 360°:8754015 | S02
INT - Détecteur 360°:Détecteur 360°:8754031 | S02
INT - Détecteur 360°:Détecteur 360°:8754032 | S02
INT - Détecteur 360°:Détecteur 360°:8754033 | S02
INT - Détecteur 360°:Détecteur 360°:8754038 | S02
INT - Détecteur 360°:Détecteur 360°:8754039 | S02
INT - Détecteur 360°:Détecteur 360°:8754040 | S02
INT - Détecteur 360°:Détecteur 360°:8754044 | S02
INT - Détecteur 360°:Détecteur 360°:8754046 | S02
INT - Détecteur 360°:Détecteur 360°:8754048 | S02
INT - Détecteur 360°:Détecteur 360°:8754059 | 01
INT - Détecteur 360°:Détecteur 360°:8754063 | S02
INT - Détecteur 360°:Détecteur 360°:8754067 | S02
INT - Détecteur 360°:Détecteur 360°:8754069 | S02
INT - Détecteur 360°:Détecteur 360°:8754070 | S02
INT - Détecteur 360°:Détecteur 360°:8754072 | S02
INT - Détecteur 360°:Détecteur 360°:8754082 | S02
INT - Détecteur 360°:Détecteur 360°:8754084 | S02
INT - Détecteur 360°:Détecteur 360°:8754086 | S02
INT - Détecteur 360°:Détecteur 360°:8754164 | S02
INT - Détecteur 360°:Détecteur 360°:8754194 | S02
INT - Détecteur 360°:Détecteur 360°:8754352 | 01
INT - Détecteur 360°:Détecteur 360°:8754390 | 01
INT - Détecteur 360°:Détecteur 360°:8754427 | 01
INT - Détecteur 360°:Détecteur 360°:8754670 | 01
INT - Détecteur 360°:Détecteur 360°:8754874 | 01
INT - Détecteur Luminosite:Détecteur 360°:8755676 | 01
INT - Détecteur Luminosite:Détecteur 360°:8798601 | S02
INT - Détecteur 360°:Détecteur 360°:8865389 | S02

# IfcFlowTerminal: Horloge secondaire (4)
Pset_DistributionFlowElementCommon - Reference: Horloge secondaire; sets with these values: 2
Pset_ProductRequirements - Category: Data Devices
Name (E_Clock_One Side Ceiling_MEPcontent:Horloge secondaire:...) | In
8318371 | S01
8318383 | S01
8748015 | S02
8748039 | S01

# IfcFlowTerminal: INT_BA Plafond 130cm (50)
Type - Material: Métal - Laiton, Bois - Noyer
Type - Pset_LightFixtureTypeCommon - TotalWattage: 100 W
Pset_DistributionFlowElementCommon - Reference: INT_BA Plafond 130cm; sets with these values: 2
Pset_ProductRequirements - Category: Lighting Fixtures
Name (II_EL_Brasseur d'air:INT_BA Plafond 130cm:...) | In
7740377 | 01
7741584 | 01
7742292 | 01
7742401 | 01
7742488 | 01
7779133 | 01
7779185 | 01
7779206 | 01
7901681 | S02
7901720 | S02
7901725 | S02
7901979 | S02
7914602 | S02
8281572 | S01
8281671 | S01
8281697 | S01
8281698 | S01
8281732 | S01
8281751 | S01
8281776 | S01
8281777 | S01
8318679 | S01
8318706 | S01
8321028 | S01
8632145 | S01
8632146 | S01
8632149 | S01
8632150 | S01
8632151 | S01
8632152 | S01
8632153 | S01
8632154 | S01
8666057 | 01
8666124 | 01
8668332 | 01
8668333 | 01
8668359 | 01
8668360 | 01
8668386 | 01
8668387 | 01
8668418 | 01
8681359 | 01
8681360 | 01
8681462 | 01
8681463 | 01
8681499 | 01
8681500 | 01
8681543 | 01
8681544 | 01
8734683 | S02

# IfcFlowTerminal: IP20 ONDULEE (90)
Pset_DistributionFlowElementCommon - Reference: IP20 ONDULEE; sets with these values: 2
Pset_ProductRequirements - Category: Electrical Fixtures
Name (INT Prise de courant:IP20 ONDULEE:...) | In
7744660 | 01
7744834 | 01
7777990 | 01
7778025 | 01
7901687 | S02
7901691 | S02
7901736 | S02
7901740 | S02
7901745 | S02
7901749 | S02
7901754 | S02
7901758 | S02
7901804 | S02
7901808 | S02
8277180 | S01
8277194 | S01
8277199 | S01
8277204 | S01
8277206 | S01
8277211 | S01
8277213 | S01
8277218 | S01
8277358 | S01
8277363 | S01
8277487 | S01
8277492 | S01
8277500 | S01
8277505 | S01
8277512 | S01
8277517 | S01
8277529 | S01
8277534 | S01
8645146 | S01
8645147 | S01
8645825 | S01
8645826 | S01
8650592 | 01
8650593 | 01
8650874 | 01
8650875 | 01
8650885 | 01
8650886 | 01
8665647 | 01
8665648 | 01
8665857 | 01
8665858 | 01
8667873 | 01
8667874 | 01
8681097 | 01
8681098 | 01
8681105 | 01
8681106 | 01
8681113 | 01
8681114 | 01
8681119 | 01
8681120 | 01
8681125 | 01
8681126 | 01
8681131 | 01
8681132 | 01
8681139 | 01
8681140 | 01
8681158 | 01
8681159 | 01
8681166 | 01
8681167 | 01
8681174 | 01
8681175 | 01
8681182 | 01
8681183 | 01
8681188 | 01
8681189 | 01
8681194 | 01
8681195 | 01
8681202 | 01
8681203 | 01
8681211 | 01
8681212 | 01
8681219 | 01
8681220 | 01
8681233 | 01
8681234 | 01
8755766 | 03_R+2_EL
8755770 | 03_R+2_EL
8755871 | 03_R+2_EL
8755970 | 03_R+2_EL
8798244 | S01
8798245 | S01
8798414 | 01
8798415 | 01

# IfcFlowTerminal: PC IP20 (141)
Pset_DistributionFlowElementCommon - Reference: PC IP20; sets with these values: 2
Pset_ProductRequirements - Category: Electrical Fixtures
Name (INT Prise de courant:PC IP20:...) | In
7744631 | 01
7744846 | 01
7777712 | 01
7777721 | 01
7777762 | 01
7777803 | 01
7778034 | 01
7778035 | 01
7877531 | 01
7901685 | S02
7901692 | S02
7901734 | S02
7901741 | S02
7901743 | S02
7901750 | S02
7901752 | S02
7901759 | S02
7901802 | S02
7901809 | S02
8277182 | S01
8277193 | S01
8277200 | S01
8277203 | S01
8277207 | S01
8277210 | S01
8277214 | S01
8277217 | S01
8277359 | S01
8277362 | S01
8277488 | S01
8277491 | S01
8277501 | S01
8277504 | S01
8277513 | S01
8277516 | S01
8277530 | S01
8277533 | S01
8645148 | S01
8645149 | S01
8645827 | S01
8645828 | S01
8645892 | S01
8645905 | S01
8645923 | S01
8650594 | 01
8650595 | 01
8650609 | 01
8650876 | 01
8650877 | 01
8650887 | 01
8650888 | 01
8665649 | 01
8665650 | 01
8665859 | 01
8665860 | 01
8665940 | 01
8665941 | 01
8666030 | 01
8667875 | 01
8667876 | 01
8681099 | 01
8681100 | 01
8681107 | 01
8681108 | 01
8681115 | 01
8681116 | 01
8681121 | 01
8681122 | 01
8681127 | 01
8681128 | 01
8681133 | 01
8681134 | 01
8681146 | 01
8681147 | 01
8681160 | 01
8681161 | 01
8681168 | 01
8681169 | 01
8681176 | 01
8681177 | 01
8681184 | 01
8681185 | 01
8681190 | 01
8681191 | 01
8681196 | 01
8681197 | 01
8681204 | 01
8681205 | 01
8681213 | 01
8681214 | 01
8681221 | 01
8681222 | 01
8681226 | 01
8681227 | 01
8681228 | 01
8681235 | 01
8681236 | 01
8715397 | 01
8715398 | 01
8715399 | 01
8715400 | 01
8715401 | 01
8715402 | 01
8715403 | 01
8715404 | 01
8715405 | 01
8715406 | 01
8715407 | 01
8715408 | 01
8715409 | 01
8715410 | 01
8715411 | 01
8715412 | 01
8715413 | 01
8715414 | 01
8715415 | 01
8715416 | 01
8715417 | 01
8715418 | 01
8715419 | 01
8715420 | 01
8715421 | 01
8715422 | S01
8715423 | S01
8715424 | S01
8715425 | S01
8715426 | S01
8715427 | S01
8715428 | S01
8715429 | S01
8715430 | S01
8755764 | 03_R+2_EL
8755771 | 03_R+2_EL
8755873 | 03_R+2_EL
8755945 | 03_R+2_EL
8798246 | S01
8798247 | S01
8798248 | S01
8798416 | 01
8798417 | 01
8798418 | 01

# IfcFlowTerminal: PC IP21 (28)
Pset_DistributionFlowElementCommon - Reference: PC IP21; sets with these values: 2
Pset_ProductRequirements - Category: Electrical Fixtures
Name (INT Prise de courant:PC IP21:...) | In
7777599 | 03_R+2_EL
7777611 | 03_R+2_EL
7876471 | S02
7876472 | S02
7876484 | S02
7902081 | S02
7902106 | S02
7902208 | S02
7902437 | S02
8270900 | S01
8297825 | S01
8317720 | S01
8319005 | S01
8319007 | S01
8319008 | S01
8319009 | S01
8319034 | S01
8645335 | S01
8645580 | S02
8674291 | 01
8674303 | 01
8742353 | 03_R+2_EL
8822402 | S01
8822413 | S01
8822533 | S01
8822545 | S01
8822557 | S01
8822569 | S01

# IfcFlowTerminal: PC IP44 (16)
Pset_DistributionFlowElementCommon - Reference: PC IP44; sets with these values: 2
Pset_ProductRequirements - Category: Electrical Fixtures
Name (INT Prise de courant:PC IP44:...) | In
7789136 | 03_R+2_EL
7789387 | S01
7792762 | S02
7792832 | S02
7792934 | S02
7793028 | S02
7793156 | S02
7796843 | S02
7876473 | S02
7876475 | S02
7913406 | S02
8666197 | 01
8719849 | S02
8747907 | S02
8747913 | S02
8747919 | S02

# IfcFlowTerminal: PC IP55 (8)
In: S02
Pset_DistributionFlowElementCommon - Reference: PC IP55; sets with these values: 2
Pset_ProductRequirements - Category: Electrical Fixtures
Name (INT Prise de courant:PC IP55:...)
8821304
8821330
8821364
8821366
8821391
8821392
8821400
8821401

# IfcFlowTerminal: PREF_BAES 01 (41)
Type - Material: Default, Escape_Sign_White_Self_Illumination, Escape_Sign_Green_Self_Illumination
Pset_DistributionFlowElementCommon - Reference: PREF_BAES 01; sets with these values: 2
Pset_ProductRequirements - Category: Lighting Fixtures
Name (II_PREF BAES:PREF_BAES 01:...) | In
7795254 | S02
7795328 | S02
7795365 | S02
7795432 | S02
7795881 | S02
7795892 | S02
7795962 | S02
7913393 | 01
7913400 | 01
7913403 | S01
8646044 | S01
8646108 | S01
8646135 | S01
8646147 | S01
8646162 | S01
8646165 | S01
8646168 | S01
8646170 | S01
8674676 | 01
8674997 | 01
8675016 | 01
8675026 | 01
8675043 | 01
8675046 | 01
8675049 | 01
8675051 | 01
8691888 | 01
8753972 | 03_R+2_EL
8753975 | 03_R+2_EL
8753982 | 03_R+2_EL
8753983 | 03_R+2_EL
8753986 | 03_R+2_EL
8753987 | 03_R+2_EL
8753990 | 03_R+2_EL
8753991 | 03_R+2_EL
8865605 | S02
8865611 | 01
8866616 | 01
8866637 | S01
8866665 | 01
8877314 | S02

# IfcFlowTerminal: PREF_BAES 02 (11)
Type - Material: Default, Escape_Sign_White_Self_Illumination, Escape_Sign_Green_Self_Illumination
Pset_DistributionFlowElementCommon - Reference: PREF_BAES 02; sets with these values: 2
Pset_ProductRequirements - Category: Lighting Fixtures
Name (II_PREF BAES:PREF_BAES 02:...) | In
7744357 | 01
7789380 | S01
7796626 | S02
8321050 | S01
8650504 | S01
8650516 | S01
8650518 | S01
8650525 | S01
8666195 | 01
8691853 | 01
8866804 | S02

# IfcFlowTerminal: Prise vidéo IP20 (6)
Pset_DistributionFlowElementCommon - Reference: Prise vidéo IP20; sets with these values: 2
Pset_ProductRequirements - Category: Data Devices
Name (INT_Prise Vidéo IP20/21:Prise vidéo IP20:...) | In
8277570 | S01
8277633 | S01
8297810 | S01
8317719 | S01
8645334 | S01
8645579 | S02

# IfcFlowTerminal: RJ45 IP20 (139)
Pset_DistributionFlowElementCommon - Reference: RJ45 IP20; sets with these values: 2
Pset_ProductRequirements - Category: Data Devices
Name (INT_Prise RJ45:RJ45 IP20:...) | In
7744688 | 01
7744747 | 01
7744756 | 01
7777885 | 01
7777958 | 01
7777965 | 01
7901688 | S02
7901689 | S02
7901690 | S02
7901737 | S02
7901738 | S02
7901739 | S02
7901746 | S02
7901747 | S02
7901748 | S02
7901755 | S02
7901756 | S02
7901757 | S02
7901805 | S02
7901806 | S02
7901807 | S02
8277183 | S01
8277192 | S01
8277195 | S01
8277201 | S01
8277202 | S01
8277205 | S01
8277208 | S01
8277209 | S01
8277212 | S01
8277215 | S01
8277216 | S01
8277219 | S01
8277360 | S01
8277361 | S01
8277364 | S01
8277489 | S01
8277490 | S01
8277493 | S01
8277502 | S01
8277503 | S01
8277506 | S01
8277514 | S01
8277515 | S01
8277518 | S01
8277531 | S01
8277532 | S01
8277535 | S01
8645143 | S01
8645145 | S01
8645822 | S01
8645824 | S01
8645922 | S01
8650589 | 01
8650591 | 01
8650871 | 01
8650873 | 01
8650883 | 01
8650884 | 01
8665645 | 01
8665646 | 01
8665855 | 01
8665856 | 01
8665937 | 01
8667871 | 01
8667872 | 01
8681095 | 01
8681096 | 01
8681103 | 01
8681104 | 01
8681111 | 01
8681112 | 01
8681117 | 01
8681118 | 01
8681123 | 01
8681124 | 01
8681129 | 01
8681130 | 01
8681145 | 01
8681148 | 01
8681156 | 01
8681157 | 01
8681164 | 01
8681165 | 01
8681172 | 01
8681173 | 01
8681180 | 01
8681181 | 01
8681186 | 01
8681187 | 01
8681192 | 01
8681193 | 01
8681200 | 01
8681201 | 01
8681209 | 01
8681210 | 01
8681217 | 01
8681218 | 01
8681225 | 01
8681231 | 01
8681232 | 01
8755767 | 03_R+2_EL
8755768 | 03_R+2_EL
8755769 | 03_R+2_EL
8755869 | 03_R+2_EL
8755917 | 03_R+2_EL
8798241 | S01
8798243 | S01
8798412 | 01
8798413 | 01
8828758 | S01
8828759 | S01
8828760 | S01
8828761 | 01
8828762 | 01
8828763 | 01
8828764 | 01
8828765 | 01
8828766 | 01
8828767 | 01
8828768 | 01
8828769 | 01
8828770 | 01
8828771 | 01
8828772 | 01
8828773 | 01
8828774 | 01
8828775 | 01
8828776 | 01
8828777 | 01
8828778 | 01
8828779 | 01
8828780 | 01
8828781 | 01
8828782 | 01
8828783 | 01
8828784 | 01
8828786 | 01
8828787 | 03_R+2_EL

# IfcFlowTerminal: RJ45 IP21 (11)
Pset_DistributionFlowElementCommon - Reference: RJ45 IP21; sets with these values: 2
Pset_ProductRequirements - Category: Data Devices
Name (INT_Prise RJ45:RJ45 IP21:...) | In
8270898 | S01
8297848 | S01
8317721 | S01
8645336 | S01
8645581 | S02
8822403 | S01
8822414 | S01
8822534 | S01
8822546 | S01
8822558 | S01
8822570 | S01

# IfcFlowTerminal: SA IP21 (7)
Pset_DistributionFlowElementCommon - Reference: SA IP21; sets with these values: 2
Pset_ProductRequirements - Category: Lighting Devices
Name (INT_Inter SA:SA IP21:...) | In
7876476 | S02
7876485 | S02
8317853 | S01
8673996 | 01
8674004 | 01
8683752 | 03_R+2_EL
8798537 | 01

# IfcFlowTerminal: SA IP44 (9)
In: S02
Pset_DistributionFlowElementCommon - Reference: SA IP44; sets with these values: 2
Pset_ProductRequirements - Category: Lighting Devices
Name (INT_Inter SA:SA IP44:...)
7793960
7794002
7794081
7794347
7794400
7794577
8723884
8723897
8723898

# IfcFlowTerminal: SL10 (5)
In: S02
Type - Material: Osram Streetlight Aluminium, Osram SL10 plastic
Pset_DistributionFlowElementCommon - Reference: SL10; sets with these values: 2
Pset_ProductRequirements - Category: Lighting Fixtures
Name (SL10:SL10:...)
8747834
8747844
8747845
8747846
8747847

# IfcFlowTerminal: Type A2_So-Tube D2 8000-840 ETDD 05 (118)
Type - Material: TRILUX_RAL9005, TRILUX_WH_4000
Pset_DistributionFlowElementCommon - Reference: Type A2_So-Tube D2 8000-840 ETDD 05; sets with these values: 2
Pset_ElementShading - Color: RAL9005 Tiefschwarz
Pset_ManufacturerTypeInformation - Manufacturer: TRILUX
Pset_ProductRequirements - Category: Lighting Fixtures
Name (II_PREF_Type A2 Tube:Type A2_So-Tube D2 8000-840 ETDD 05:...) | In
7901673 | S02
7901679 | S02
7901718 | S02
7901719 | S02
7901723 | S02
7901724 | S02
7901902 | S02
8281313 | S01
8281360 | S01
8281379 | S01
8281695 | S01
8281696 | S01
8281786 | S01
8318129 | S02
8318138 | S02
8318201 | S02
8318212 | S02
8318221 | S02
8318230 | S02
8318244 | S02
8318246 | S02
8318248 | S02
8318250 | S02
8318252 | S02
8318254 | S02
8318572 | S01
8318608 | S01
8318626 | S01
8319157 | S01
8319195 | S02
8320982 | S02
8632143 | S01
8632144 | S01
8632147 | S01
8632148 | S01
8632155 | S01
8632162 | S01
8632166 | S01
8632167 | S01
8632168 | S01
8632169 | S01
8632171 | S01
8632175 | S01
8632177 | S01
8632179 | S01
8632181 | S01
8632204 | S01
8632205 | S01
8650686 | 01
8650687 | 01
8650688 | 01
8650811 | 01
8650812 | 01
8667969 | 01
8667970 | 01
8668206 | 01
8668207 | 01
8668221 | 01
8668222 | 01
8668234 | 01
8668235 | 01
8668245 | 01
8668246 | 01
8668327 | 01
8668328 | 01
8668354 | 01
8668355 | 01
8668381 | 01
8668382 | 01
8668447 | 01
8668458 | 01
8668472 | 01
8668496 | 01
8674234 | 01
8674521 | 01
8681350 | S02
8681354 | S02
8681355 | S02
8681362 | S02
8681396 | S02
8681457 | S02
8681465 | S02
8681466 | S02
8681491 | S02
8681495 | S02
8681502 | S02
8681538 | S02
8681539 | S02
8681547 | 01
8683758 | S02
8683759 | S02
8683763 | S02
8683764 | S02
8683768 | S02
8688659 | 01
8688800 | S02
8688801 | S02
8688805 | S02
8688806 | S02
8688810 | S02
8688830 | S02
8688831 | S02
8688835 | S02
8688836 | S02
8688840 | S02
8688980 | S02
8691844 | S02
8691845 | S02
8734212 | 01
8755505 | S02
8755559 | S02
8755570 | S02
8755578 | S02
8798368 | S02
8798577 | 01
8798578 | 01
8798621 | 01
8822909 | 01

# IfcFlowTerminal: Type C_TUBOLUCE 7512 OP L662 2660LM (84)
Pset_DistributionFlowElementCommon - Reference: Type C_TUBOLUCE 7512 OP L662 2660LM; sets with these values: 2
Pset_ManufacturerTypeInformation - Manufacturer: Metalmek
Pset_ProductRequirements - Category: Lighting Fixtures
Name (II_PREF_Type C Cylindre ext:Type C_TUBOLUCE 7512 OP L662 2660LM:...) | In
7797644 | S02
7797806 | S02
7797814 | S02
7797822 | S02
7797830 | S02
7797890 | S02
7797891 | S02
7797892 | S02
7797893 | S02
7797894 | S02
7797913 | S02
7797921 | S02
7797929 | S02
7797939 | S02
7811123 | S02
7811149 | S02
7811159 | S02
7899299 | 01
7899314 | 01
7899315 | 01
7899833 | 01
7910440 | S02
7910441 | S02
7910442 | S01
7910443 | S01
7910444 | 01
7910445 | 01
7910447 | S01
7910448 | S01
7910461 | S01
7910462 | S01
8280951 | S01
8280953 | S01
8280955 | S01
8280957 | S01
8280959 | S01
8280961 | S01
8280963 | S01
8280965 | S01
8280967 | S01
8280969 | S01
8280971 | S01
8280973 | S01
8281282 | S01
8281283 | S01
8281284 | S01
8281285 | S01
8281286 | S01
8281287 | S01
8281288 | S01
8281289 | S01
8281290 | S01
8281291 | S01
8281292 | S01
8281293 | S01
8674661 | S01
8674662 | S01
8674663 | S01
8674664 | S01
8674665 | S01
8674666 | S01
8674667 | S01
8674668 | S01
8674669 | S01
8674670 | S01
8674671 | S01
8674672 | S01
8674927 | S01
8674928 | S01
8674929 | S01
8674930 | S01
8674931 | S01
8674932 | S01
8674933 | S01
8674934 | S01
8674935 | S01
8674936 | S01
8674937 | S01
8674938 | S01
8691886 | S01
8719838 | S01
8755390 | S01
8865361 | S02
8865374 | S02

# IfcFlowTerminal: Type E_Spot (31)
Type - Classification: D5020200 (Uniformat); Material: Aluminium-Fasual-Aluminium_Blanc, Glass-Fasual-Vitrage_Clair, Aluminum-Fasual-Aluminum_Anodisé, Polycarbonate-Fasual-Polycarbonate_Clair
Pset_DistributionFlowElementCommon - Reference: Type E_Spot; sets with these values: 2
Pset_ManufacturerTypeInformation - Manufacturer: FASUAL
Pset_ProductRequirements - Category: Lighting Fixtures
Name (II_PREF_Type E_Spot LED:Type E_Spot:...) | In
7741705 | 01
7742182 | 01
7742196 | 01
7742534 | 01
7743602 | 01
7743644 | 01
7743663 | 01
7743682 | 01
7743703 | 01
7789358 | S01
7789362 | S01
7789363 | S01
7789365 | S01
7791233 | S01
7791303 | S01
7791399 | S01
7791401 | S01
7791411 | S01
7791412 | S01
7796153 | S02
7796360 | S02
7796443 | S02
7796490 | S02
7796509 | S02
8666173 | 01
8666175 | 01
8666176 | 01
8666177 | 01
8666178 | 01
8666180 | 01
8798327 | S01

# IfcFlowTerminal: VV IP21 (16)
Pset_DistributionFlowElementCommon - Reference: VV IP21; sets with these values: 2
Pset_ProductRequirements - Category: Lighting Devices
Name (INT_Inter VV:VV IP21:...) | In
7876477 | S02
7876480 | S02
7876482 | S02
7876502 | S02
7901695 | S02
7901700 | S02
7901710 | S02
7901712 | S02
7901713 | S02
7901714 | S02
8317731 | S01
8317737 | S01
8317769 | S01
8317824 | S01
8674549 | 01
8674556 | 01

# IfcFlowTerminal: VV IP44 (2)
In: S02
Pset_DistributionFlowElementCommon - Reference: VV IP44; sets with these values: 2
Pset_ProductRequirements - Category: Lighting Devices
Name (INT_Inter VV:VV IP44:...)
7876478
7876479

# IfcSlab: Floor:Bureau, Floor:Bureau:8750606
In: S01
Type - PredefinedType: FLOOR; Material: Bois 0.025 m
Type - Pset_ElementShading - Roughness: 0.9144 m
Type - Pset_ProductRequirements - Category: Floors
Type - Pset_QuantityTakeOff - Reference: Bureau
Type - Pset_ReinforcementBarPitchOfSlab - Reference: Bureau
Type - Pset_SlabCommon - Reference: Bureau; IsExternal: no; ThermalTransmittance: 4.8 kg/K/s3
Pset_QuantityTakeOff - sets with these values: 2
Pset_SlabCommon - IsExternal: yes; LoadBearing: no; PitchAngle: 0 deg

# IfcSlab: Floor:Bureau, Floor:Bureau:8750307
In: 01
Type - PredefinedType: FLOOR; Material: Bois 0.025 m
Type - Pset_ElementShading - Roughness: 0.9144 m
Type - Pset_ProductRequirements - Category: Floors
Type - Pset_QuantityTakeOff - Reference: Bureau
Type - Pset_ReinforcementBarPitchOfSlab - Reference: Bureau
Type - Pset_SlabCommon - Reference: Bureau; ThermalTransmittance: 4.8 kg/K/s3; IsExternal: no
Pset_QuantityTakeOff - sets with these values: 2
Pset_SlabCommon - IsExternal: yes; LoadBearing: no; PitchAngle: 0 deg
